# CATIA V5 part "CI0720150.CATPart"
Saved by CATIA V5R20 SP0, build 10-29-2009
Part number: CI0720150
Bounding box of the stored display mesh (mm): x -19 to 19, y -15.457 to 180, z -19.154 to 22.707
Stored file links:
  C:\Users\Raffaele\Desktop\3D X SITO CF\BOLEX\19-INCLINED ASSEMBLY REF_CI\CI0720150.CATPart

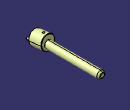
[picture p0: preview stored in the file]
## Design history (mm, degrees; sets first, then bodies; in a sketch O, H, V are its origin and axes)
Set1
  DatumSurface1 to DatumSurface16 "MANIFOLD_SOLID_BREP #387"
  DatumSurface17 to DatumSurface39 "MANIFOLD_SOLID_BREP #1116"
Body1 (main body)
